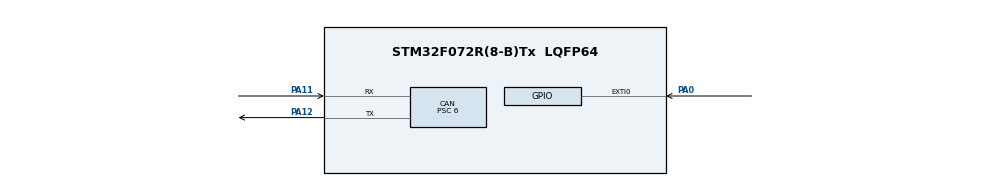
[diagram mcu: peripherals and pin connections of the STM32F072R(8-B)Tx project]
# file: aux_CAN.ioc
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CAN.BS1=CAN_BS1_13TQ
CAN.BS2=CAN_BS2_2TQ
CAN.CalculateBaudRate=500000
CAN.CalculateTimeBit=2000.00
CAN.CalculateTimeQuantum=125.0
CAN.Mode=CAN_MODE_LOOPBACK
CAN.Prescaler=6
Mcu.Family=STM32F0
Mcu.Name=STM32F072R(8-B)Tx
Mcu.Package=LQFP64
NVIC.CEC_CAN_IRQn=true\:2\:0\:true\:false\:true\:true\:true
NVIC.EXTI0_1_IRQn=true\:1\:0\:true\:false\:true\:true\:true
PA0.Signal=GPXTI0
PA11.Mode=CAN_Activate
PA11.Signal=CAN_RX
PA12.Mode=CAN_Activate
PA12.Signal=CAN_TX
PF0-OSC_IN.Mode=HSE-External-Oscillator
PF0-OSC_IN.Signal=RCC_OSC_IN
PF1-OSC_OUT.Mode=HSE-External-Oscillator
PF1-OSC_OUT.Signal=RCC_OSC_OUT
ProjectManager.HeapSize=0x200
ProjectManager.StackSize=0x400
ProjectManager.TargetToolchain=STM32CubeIDE
RCC.AHBFreq_Value=48000000
RCC.APB1Freq_Value=48000000
RCC.APB1TimFreq_Value=48000000
RCC.HCLKFreq_Value=48000000
RCC.SYSCLKFreq_VALUE=48000000
RCC.SYSCLKSource=RCC_SYSCLKSOURCE_HSI48
board=custom

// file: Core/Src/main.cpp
/* USER CODE BEGIN Header */

/*
 * Taylor Gerke
 * Solar Gators Auxiliary Team
 * May 21, 2021
 *
 * This basic program is a proof of concept of ST's HAL functions for CAN communication.
 * There are two bytes in this program, a and r. Byte a is incremented with each cycle of
 * the 'while' loop and sent out over CAN. Byte r receives the value of byte a over CAN and is
 * updated accordingly.
 *
 */

/**
  ******************************************************************************
  * @file           : main.c
  * @brief          : Main program body
  ******************************************************************************
  * @attention
  *
  * <h2><center>&copy; Copyright (c) 2021 STMicroelectronics.
  * All rights reserved.</center></h2>
  *
  * This software component is licensed by ST under BSD 3-Clause license,
  * the "License"; You may not use this file except in compliance with the
  * License. You may obtain a copy of the License at:
  *                        opensource.org/licenses/BSD-3-Clause
  *
  ******************************************************************************
  */
/* USER CODE END Header */
#include "main.h"

CAN_HandleTypeDef hcan;

/* USER CODE BEGIN PV */
CAN_TxHeaderTypeDef pHeader;
CAN_RxHeaderTypeDef pRxHeader;
uint32_t TxMailbox;
uint8_t a,r;
CAN_FilterTypeDef sFilterConfig;
/* USER CODE END PV */

void SystemClock_Config(void);
static void MX_GPIO_Init(void);
static void MX_CAN_Init(void);

int main(void)
{

  /* MCU Configuration--------------------------------------------------------*/

  /* Reset of all peripherals, Initializes the Flash interface and the Systick. */
  HAL_Init();

  /* Configure the system clock */
  SystemClock_Config();

  /* Initialize all configured peripherals */
  MX_GPIO_Init();
  MX_CAN_Init();
  /* USER CODE BEGIN 2 */
  HAL_CAN_Start(&hcan);
  HAL_CAN_ActivateNotification(&hcan, CAN_IT_RX_FIFO0_MSG_PENDING);

  pHeader.DLC = 1;
  pHeader.IDE = CAN_ID_STD;
  pHeader.RTR = CAN_RTR_DATA;
  pHeader.StdId = 0x244;

  sFilterConfig.FilterFIFOAssignment=CAN_FILTER_FIFO0;

  // The CAN filter is set to only receive from CAN messages of identifier 0x3FF, or 1023.
  // This is the auxiliary CAN identifier for Sunbreaker.
  sFilterConfig.FilterIdHigh=0x3FF;
  sFilterConfig.FilterIdLow=0x3FF;
  sFilterConfig.FilterMaskIdHigh=0;
  sFilterConfig.FilterMaskIdLow=0;
  sFilterConfig.FilterScale=CAN_FILTERSCALE_32BIT;
  sFilterConfig.FilterActivation=ENABLE;
  HAL_CAN_ConfigFilter(&hcan, &sFilterConfig);

  HAL_CAN_Start(&hcan);
  HAL_CAN_ActivateNotification(&hcan, CAN_IT_RX_FIFO0_MSG_PENDING);
  /* USER CODE END 2 */

  /* Infinite loop */
  while (1)
  {

	  // Only send a new TX message if the outgoing mailbox is empty
	  if (HAL_CAN_IsTxMessagePending(&hcan,TxMailbox) == false) {

		  HAL_CAN_AddTxMessage(&hcan, &pHeader, &a, &TxMailbox);

	  }

	  a++;

  }
}

void SystemClock_Config(void)
{
  RCC_OscInitTypeDef RCC_OscInitStruct = {0};
  RCC_ClkInitTypeDef RCC_ClkInitStruct = {0};

  /** Initializes the RCC Oscillators according to the specified parameters
  * in the RCC_OscInitTypeDef structure.
  */
  RCC_OscInitStruct.OscillatorType = RCC_OSCILLATORTYPE_HSI;
  RCC_OscInitStruct.HSIState = RCC_HSI_ON;
  RCC_OscInitStruct.HSICalibrationValue = RCC_HSICALIBRATION_DEFAULT;
  RCC_OscInitStruct.PLL.PLLState = RCC_PLL_NONE;
  if (HAL_RCC_OscConfig(&RCC_OscInitStruct) != HAL_OK)
  {
    Error_Handler();
  }
  /** Initializes the CPU, AHB and APB buses clocks
  */
  RCC_ClkInitStruct.ClockType = RCC_CLOCKTYPE_HCLK|RCC_CLOCKTYPE_SYSCLK
                              |RCC_CLOCKTYPE_PCLK1;
  RCC_ClkInitStruct.SYSCLKSource = RCC_SYSCLKSOURCE_HSI;
  RCC_ClkInitStruct.AHBCLKDivider = RCC_SYSCLK_DIV1;
  RCC_ClkInitStruct.APB1CLKDivider = RCC_HCLK_DIV1;

  if (HAL_RCC_ClockConfig(&RCC_ClkInitStruct, FLASH_LATENCY_0) != HAL_OK)
  {
    Error_Handler();
  }
}

static void MX_CAN_Init(void)
{

	hcan.Instance = CAN;
	  hcan.Init.Prescaler = 6;
	  hcan.Init.Mode = CAN_MODE_LOOPBACK;
	  hcan.Init.SyncJumpWidth = CAN_SJW_1TQ;
	  hcan.Init.TimeSeg1 = CAN_BS1_13TQ;
	  hcan.Init.TimeSeg2 = CAN_BS2_2TQ;
	  hcan.Init.TimeTriggeredMode = DISABLE;
	  hcan.Init.AutoBusOff = DISABLE;
	  hcan.Init.AutoWakeUp = DISABLE;
	  hcan.Init.AutoRetransmission = DISABLE;
	  hcan.Init.ReceiveFifoLocked = DISABLE;
	  hcan.Init.TransmitFifoPriority = DISABLE;
  if (HAL_CAN_Init(&hcan) != HAL_OK)
  {
    Error_Handler();
  }

}

static void MX_GPIO_Init(void)
{
  GPIO_InitTypeDef GPIO_InitStruct = {0};

  /* GPIO Ports Clock Enable */
  __HAL_RCC_GPIOF_CLK_ENABLE();
  __HAL_RCC_GPIOA_CLK_ENABLE();

  /*Configure GPIO pin : PA0 */
  GPIO_InitStruct.Pin = GPIO_PIN_13;
  GPIO_InitStruct.Mode = GPIO_MODE_IT_RISING;
  GPIO_InitStruct.Pull = GPIO_NOPULL;
  HAL_GPIO_Init(GPIOC, &GPIO_InitStruct);

  /* EXTI interrupt init*/
  HAL_NVIC_SetPriority(EXTI0_1_IRQn, 1, 0);
  HAL_NVIC_EnableIRQ(EXTI0_1_IRQn);

}

void Error_Handler(void)
{
  __disable_irq();
  while (1)
  {
  }
}

/************************ (C) COPYRIGHT STMicroelectronics *****END OF FILE****/
